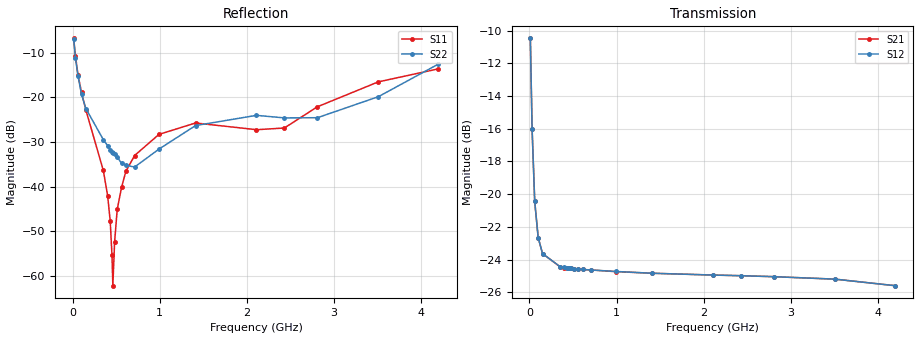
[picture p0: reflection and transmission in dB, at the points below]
! Integrated Device Technology
! Corporate Headquarters
! 6024 Silver Creek Valley Road
! San Jose, CA 95138  USA
! Phone:  1-408-284-8200
! Toll Free:  1-800-223-1366
! Webpage:  http://www.idt.com/
! Timing and RF Division
! 515 Groton Road, Suite 102
! Westford, MA 01886-6024
! Device:  F1950
! Description: 7-bit 0.25 dB Digital Step Attenuator
! Frequency:  150.0 -  4000.00 MHz
! Package:  4x4 mm Thin QFN Plastic Package: 24 pin
! Ports:  2 RF, 12 DC
!  Pin  1  = D0
!  Pin  2  = VDD
!  Pin  3  = Vmode
!  Pin  4  = GND
!  Pin  5  = RF1  =  Port 1
!  Pin  6  = GND
!  Pin  7  = GND
!  Pin  8  = GND
!  Pin  9  = GND
!  Pin 10  = GND
!  Pin 11  = GND
!  Pin 12  = GND
!  Pin 13  = GND
!  Pin 14  = RF2  =  Port 2
!  Pin 15  = GND
!  Pin 16  = LE
!  Pin 17  = CLK
!  Pin 18  = DATE
!  Pin 19  = D6
!  Pin 20  = D5
!  Pin 21  = D4
!  Pin 22  = D3
!  Pin 23  = D2
!  Pin 24  = D1
! State:  95
! Atten State:  23.75 dB
! Voltage:  +5.00 Volts
! Current:  Not Measured mA
! Data:  The device was measured on a the F195X evaluation board which has
!  individual transmission lines to the RF pins.  Data was collected
!  using a calibrated network analyzer.  The evaluation board was
!  de-embedded using a TRL calibration technique.
!  The reference plane is the edge of the package pin.
! Misc:  Board 2019
!  Action Tracker AT0250
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# GHz S dB R 50
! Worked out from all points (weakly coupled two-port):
!   420 points, 10 MHz to 4.2 GHz, reference 50 ohm
!   highest |S21| = -10.48 dB at 10 MHz (marker M1); lowest = -25.6 dB at 4.2 GHz (marker M2)
!   lowest |S11| = -62.2 dB at 460 MHz (marker M3), VSWR 1.00, Z = 49.9 - j0.0543 ohm
!   |S11| at or under -10 dB: 26.53 MHz to end of sweep
!   |S22| runs from -35.9 to -6.9 dB; largest |S21 - S12| = 0.00011
!   S11 on the Smith chart (normalised r, x): 10 MHz: 2.04, -1.06; 30 MHz: 1.30, -0.63; 60 MHz: 1.11, -0.36; 430 MHz: 1.00, -0.01; 4.2 GHz: 0.69, +0.17
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0.01  -6.74 -26.3  -10.48 -32.8  -10.48 -32.8  -6.91 -28.7
0.03  -10.64 -49.5  -16.00 -48.8  -16.00 -48.8  -11.06 -51.6
0.06  -15.01 -62.8  -20.44 -43.7  -20.44 -43.7  -15.27 -63.9
0.1  -18.87 -69.6  -22.66 -33.2  -22.66 -33.2  -19.29 -69.0
0.15  -22.82 -71.4  -23.64 -25.2  -23.64 -25.2  -22.49 -72.9
0.35  -36.36 -66.6  -24.44 -15.3  -24.43 -15.3  -29.46 -82.2
0.4  -42.03 -67.9  -24.49 -14.7  -24.48 -14.7  -30.84 -83.7
0.43  -47.84 -74.5  -24.51 -14.4  -24.51 -14.5  -31.71 -86.6
0.45  -55.45 -89.0  -24.53 -14.3  -24.52 -14.3  -32.23 -89.7
0.46  -62.25 -135.2  -24.53 -14.3  -24.53 -14.3  -32.43 -91.4
0.48  -52.49 138.5  -24.54 -14.2  -24.54 -14.2  -32.76 -94.3
0.51  -45.14 133.6  -24.56 -14.1  -24.56 -14.1  -33.33 -96.9
0.56  -40.16 131.4  -24.58 -14.1  -24.58 -14.1  -34.81 -104.5
0.61  -36.57 133.6  -24.61 -14.2  -24.61 -14.2  -35.23 -116.2
0.71  -33.03 135.9  -24.64 -14.6  -24.64 -14.6  -35.62 -137.1
0.99  -28.29 146.1  -24.74 -16.6  -24.73 -16.6  -31.59 179.3
1.41  -25.73 162.2  -24.84 -20.3  -24.84 -20.4  -26.31 159.8
2.11  -27.24 156.7  -24.95 -27.7  -24.95 -27.8  -24.02 141.4
2.43  -26.86 124.4  -24.99 -31.0  -24.99 -31.0  -24.59 130.4
2.81  -22.09 104.0  -25.05 -35.5  -25.05 -35.5  -24.55 114.8
3.51  -16.50 116.6  -25.20 -43.1  -25.20 -43.2  -19.83 112.4
4.2  -13.58 145.4  -25.60 -48.7  -25.60 -48.7  -12.51 126.8
